One B-rep face of a CAD part: STEP entity #118.
In plain terms, the planar face has unit normal (1, 0, 0).
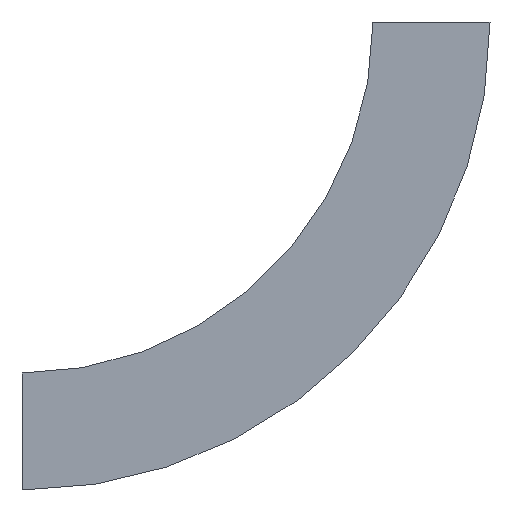
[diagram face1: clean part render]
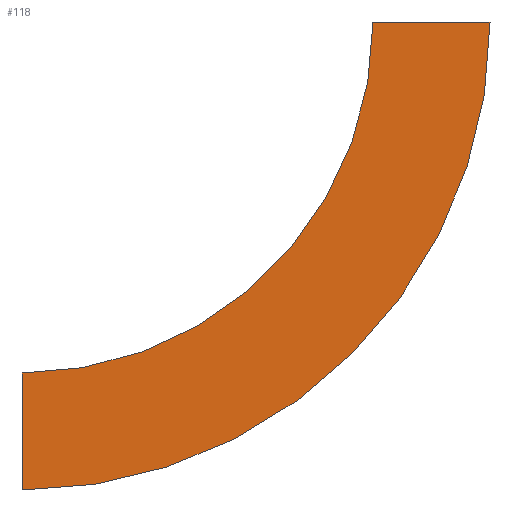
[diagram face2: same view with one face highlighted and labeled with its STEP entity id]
Its self-contained STEP definition (entity closure, numbers rounded to 3 decimals):
#2 = CARTESIAN_POINT ( 'NONE',  ( 0., 300., 0. ) ) ;
#10 = EDGE_CURVE ( 'NONE', #271, #286, #264, .T. ) ;
#37 = CARTESIAN_POINT ( 'NONE',  ( 0., 300., -300. ) ) ;
#53 = EDGE_CURVE ( 'NONE', #243, #286, #266, .T. ) ;
#59 = EDGE_LOOP ( 'NONE', ( #323, #111, #516, #533 ) ) ;
#111 = ORIENTED_EDGE ( 'NONE', *, *, #364, .F. ) ;
#118 = ADVANCED_FACE ( 'NONE', ( #540 ), #144, .F. ) ;
#125 = CARTESIAN_POINT ( 'NONE',  ( 0., 300., 0. ) ) ;
#144 = PLANE ( 'NONE',  #188 ) ;
#162 = DIRECTION ( 'NONE',  ( 0., 1., 0. ) ) ;
#168 = VECTOR ( 'NONE', #162, 1000. ) ;
#188 = AXIS2_PLACEMENT_3D ( 'NONE', #452, #313, #496 ) ;
#207 = AXIS2_PLACEMENT_3D ( 'NONE', #125, #340, #386 ) ;
#210 = CARTESIAN_POINT ( 'NONE',  ( 0., 0., 0. ) ) ;
#220 = VECTOR ( 'NONE', #433, 1000. ) ;
#228 = CARTESIAN_POINT ( 'NONE',  ( 0., -100., 0. ) ) ;
#243 = VERTEX_POINT ( 'NONE', #210 ) ;
#256 = CARTESIAN_POINT ( 'NONE',  ( 0., 300., -400. ) ) ;
#264 = LINE ( 'NONE', #256, #220 ) ;
#266 = CIRCLE ( 'NONE', #370, 300. ) ;
#271 = VERTEX_POINT ( 'NONE', #500 ) ;
#286 = VERTEX_POINT ( 'NONE', #37 ) ;
#294 = DIRECTION ( 'NONE',  ( 0., -1., 0. ) ) ;
#313 = DIRECTION ( 'NONE',  ( -1., 0., 0. ) ) ;
#323 = ORIENTED_EDGE ( 'NONE', *, *, #53, .F. ) ;
#340 = DIRECTION ( 'NONE',  ( 1., 0., 0. ) ) ;
#364 = EDGE_CURVE ( 'NONE', #567, #243, #404, .T. ) ;
#370 = AXIS2_PLACEMENT_3D ( 'NONE', #2, #377, #294 ) ;
#377 = DIRECTION ( 'NONE',  ( 1., 0., 0. ) ) ;
#386 = DIRECTION ( 'NONE',  ( 0., -1., 0. ) ) ;
#396 = CIRCLE ( 'NONE', #207, 400. ) ;
#404 = LINE ( 'NONE', #547, #168 ) ;
#433 = DIRECTION ( 'NONE',  ( 0., 0., 1. ) ) ;
#452 = CARTESIAN_POINT ( 'NONE',  ( 0., -100., 0. ) ) ;
#460 = EDGE_CURVE ( 'NONE', #567, #271, #396, .T. ) ;
#496 = DIRECTION ( 'NONE',  ( 0., 0., 1. ) ) ;
#500 = CARTESIAN_POINT ( 'NONE',  ( 0., 300., -400. ) ) ;
#516 = ORIENTED_EDGE ( 'NONE', *, *, #460, .T. ) ;
#533 = ORIENTED_EDGE ( 'NONE', *, *, #10, .T. ) ;
#540 = FACE_OUTER_BOUND ( 'NONE', #59, .T. ) ;
#547 = CARTESIAN_POINT ( 'NONE',  ( 0., -100., 0. ) ) ;
#567 = VERTEX_POINT ( 'NONE', #228 ) ;
